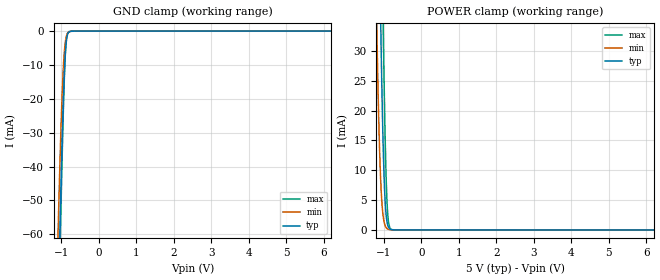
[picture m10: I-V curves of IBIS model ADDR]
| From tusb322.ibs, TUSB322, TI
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|   Model
[Model]   ADDR
Model_type   Input
Vinl = 1.5
Vinh = 3.5
|   typ   min   max
C_comp   0.490pF   0.431pF   0.550pF
[Voltage Range]   5   4.999   5.001
[Temperature Range]   27   105   -40
[Power Clamp Reference]   5   4.999   5.001
[GND Clamp Reference]   0   0   0
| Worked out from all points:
|   GND clamp passes 1 mA (typ) near -0.83 V on its own axis
|   POWER clamp passes 1 mA (typ) near -0.90 V on its own axis
[GND Clamp]
|   Voltage   I(typ)   I(min)   I(max)
-5V       -2.345A    -2.242A    -2.422A
-1.085V   -81.53mA   -58.82mA   -91.1mA
-1.04V    -59.7mA    -40.13mA   -67.51mA
-1.025V   -52.74mA   -34.39mA   -59.89mA
-995mV    -39.45mA   -23.95mA   -45.16mA
-965mV    -27.34mA   -15.22mA   -31.42mA
-935mV    -16.94mA   -8.64mA    -19.24mA
-905mV    -8.974mA   -4.353mA   -9.597mA
-890mV    -6.086mA   -2.973mA   -6.094mA
-860mV    -2.447mA   -1.319mA   -1.966mA
-800mV    -305.5uA   -253.3uA   -162.3uA
10V       0A         0A         0A
[POWER Clamp]
|   Voltage   I(typ)   I(min)   I(max)
-5V       2.317A     2.221A     2.385A
-1.19V    81.56mA    34.73mA    119mA
-1.13V    53.93mA    17.15mA    87.53mA
-1.085V   35.48mA    8.501mA    65.05mA
-1.025V   15.94mA    2.688mA    37.58mA
-1.01V    12.3mA     1.962mA    31.41mA
-980mV    6.749mA    1.027mA    20.31mA
-935mV    2.285mA    381.5uA    8.075mA
-905mV    1.027mA    197.9uA    3.509mA
-875mV    449.9uA    104.6uA    1.324mA
-710mV    14.24uA    11.36uA    15.82uA
10V       0A         0A         0A
